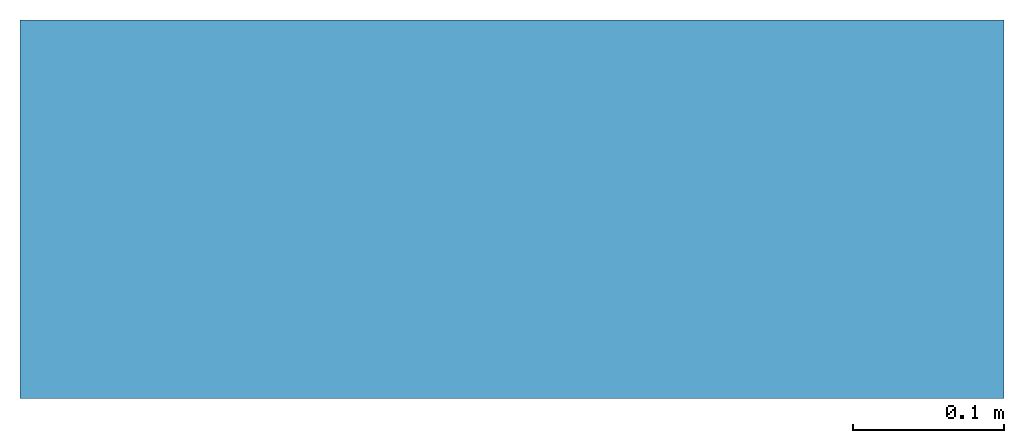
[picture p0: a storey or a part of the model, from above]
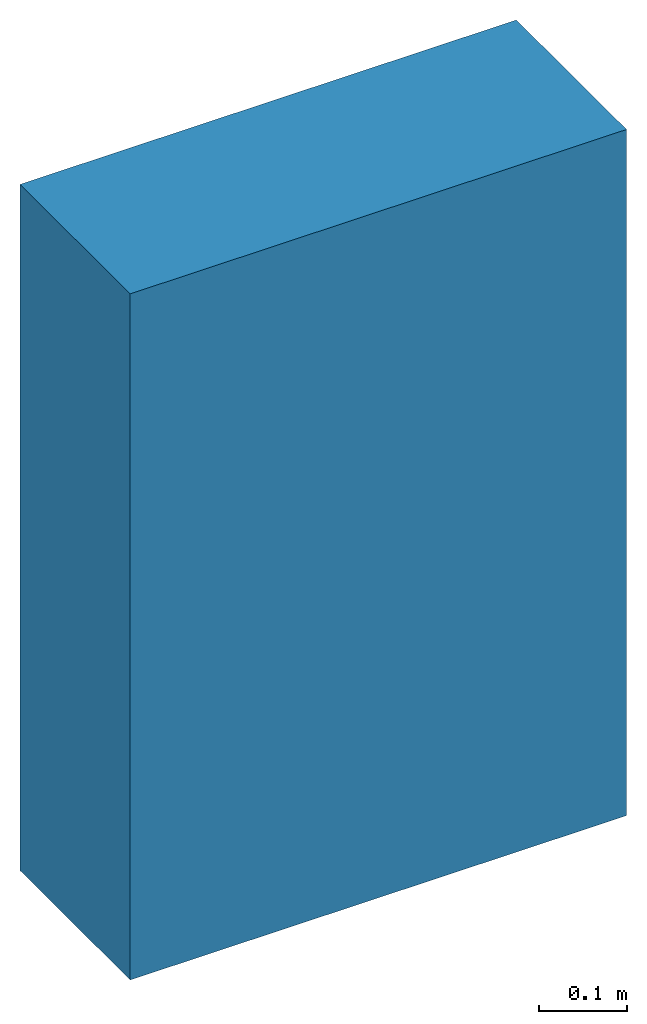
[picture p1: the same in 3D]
Properties of the parts of a building model (IFC2X3), part 1 of 2

# File
Description: ViewDefinition [CoordinationView]
File name: VA001-350.101.1 (EDITED).ifc (Edited by Naviate Simple BIM 2022 version 6)
Time: 2026-03-20T14:23:33+01:00
Written by: ODA SDAI 22.12
Made in: Autodesk Revit 23.1.90.15 (ENU) - IFC 23.3.1.0

# IfcProject
LongName: Trondheim Lufthavn Værnes; Phase: TU 2013

# IfcSite, Default
RefLatitude: 59, 54, 57, 601318; RefLongitude: 10, 44, 59, 999999; RefElevation: 0 mm
Data - Ideate BIMLink: <?xml version="1.0" encoding="utf-8"?><application version="3"> <links> <link> <name>Casework Types</name> <description></description> <elements>CaseworkTypes</elements> <phase>Fase 2</phase> <phase_filter>None</phase_filter> <properties> <property> <name>Id</name> <lookup_1_type></lookup_1_type> <lookup_1_id></lookup_1_id> <type>BUILT_IN_PARAMETER</type> <id>ID_PARAM</id> </property> <property> <name>Family Name</name> <lookup_1_type></lookup_1_type> <lookup_1_id></lookup_1_id> <type>CALCULATED_PROPERTY</type> <id>FamilyName</id> </property> <property> <name>Type Name</name> <lookup_1_type></lookup_1_type> <lookup_1_id></lookup_1_id> <type>CALCULATED_PROPERTY</type> <id>TypeName</id> </property> </properties> </link> <link> <name>Window Types</name> <description></description> <elements>WindowTypes</elements> <phase>Fase 2</phase> <phase_filter>None</phase_filter> <properties> <property> <name>Id</name> <lookup_1_type></lookup_1_type> <lookup_1_id></lookup_1_id> <type>BUILT_IN_PARAMETER</type> <id>ID_PARAM</id> </property> <property> <name>Family Name</name> <lookup_1_type></lookup_1_type> <lookup_1_id></lookup_1_id> <type>CALCULATED_PROPERTY</type> <id>FamilyName</id> </property> <property> <name>Type Name</name> <lookup_1_type></lookup_1_type> <lookup_1_id></lookup_1_id> <type>CALCULATED_PROPERTY</type> <id>TypeName</id> </property> </properties> </link> <link> <name>Wall Types</name> <description></description> <elements>WallTypes</elements> <phase>Fase 1</phase> <phase_filter>Show Complete</phase_filter> <properties> <property> <name>Id</name> <lookup_1_type></lookup_1_type> <lookup_1_id></lookup_1_id> <type>BUILT_IN_PARAMETER</type> <id>ID_PARAM</id> </property> <property> <name>Family Name</name> <lookup_1_type></lookup_1_type> <lookup_1_id></lookup_1_id> <type>BUILT_IN_PARAMETER</type> <id>SYMBOL_FAMILY_NAME_PARAM</id> </property> <property> <name>Type Name</name> <lookup_1_type></lookup_1_type> <lookup_1_id></lookup_1_id> <type>CALCULATED_PROPERTY</type> <id>TypeName</id> </property> </properties> </link> <link> <name>Structural Framing Types</name> <description></description> <elements>StructuralFramingTypes</elements> <phase>Fase 2</phase> <phase_filter>None</phase_filter> <properties> <property> <name>Id</name> <lookup_1_type></lookup_1_type> <lookup_1_id></lookup_1_id> <type>BUILT_IN_PARAMETER</type> <id>ID_PARAM</id> </property> <property> <name>Family Name</name> <lookup_1_type></lookup_1_type> <lookup_1_id></lookup_1_id> <type>CALCULATED_PROPERTY</type> <id>FamilyName</id> </property> <property> <name>Type Name</name> <lookup_1_type></lookup_1_type> <lookup_1_id></lookup_1_id> <type>CALCULATED_PROPERTY</type> <id>TypeName</id> </property> </properties> </link> <link> <name>Structural Foundation Types</name> <description></description> <elements>StructuralFoundationTypes</elements> <phase>Fase 2</phase> <phase_filter>None</phase_filter> <properties> <property> <name>Id</name> <lookup_1_type></lookup_1_type> <lookup_1_id></lookup_1_id> <type>BUILT_IN_PARAMETER</type> <id>ID_PARAM</id> </property> <property> <name>Family Name</name> <lookup_1_type></lookup_1_type> <lookup_1_id></lookup_1_id> <type>CALCULATED_PROPERTY</type> <id>FamilyName</id> </property> <property> <name>Type Name</name> <lookup_1_type></lookup_1_type> <lookup_1_id></lookup_1_id> <type>CALCULATED_PROPERTY</type> <id>TypeName</id> </property> </properties> </link> <link> <name>Structural Column Types</name> <description></description> <elements>StructuralColumnTypes</elements> <phase>Fase 2</phase> <phase_filter>None</phase_filter> <properties> <property> <name>Id</name> <lookup_1_type></lookup_1_type> <lookup_1_id></lookup_1_id> <type>BUILT_IN_PARAMETER</type> <id>ID_PARAM</id> </property> <property> <name>Family Name</name> <lookup_1_type></lookup_1_type> <lookup_1_id></lookup_1_id> <type>CALCULATED_PROPERTY</type> <id>FamilyName</id> </property> <property> <name>Type Name</name> <lookup_1_type></lookup_1_type> <lookup_1_id></lookup_1_id> <type>CALCULATED_PROPERTY</type> <id>TypeName</id> </property> </properties> </link> <link> <name>Stair Types</name> <description></description> <elements>StairTypes</elements> <phase>Fase 2</phase> <phase_filter>None</phase_filter> <properties> <property> <name>Id</name> <lookup_1_type></lookup_1_type> <lookup_1_id></lookup_1_id> <type>BUILT_IN_PARAMETER</type> <id>ID_PARAM</id> </property> <property> <name>Family Name</name> <lookup_1_type></lookup_1_type> <lookup_1_id></lookup_1_id> <type>BUILT_IN_PARAMETER</type> <id>ALL_MODEL_FAMILY_NAME</id> </property> <property> <name>Type Name</name> <lookup_1_type></lookup_1_type> <lookup_1_id></lookup_1_id> <type>CALCULATED_PROPERTY</type> <id>TypeName</id> </property> </properties> </link> <link> <name>Specialty Equipment Types</name> <description></description> <elements>SpecialtyEquipmentTypes</elements> <phase>Fase 2</phase> <phase_filter>None</phase_filter> <properties> <property> <name>Id</name> <lookup_1_type></lookup_1_type> <lookup_1_id></lookup_1_id> <type>BUILT_IN_PARAMETER</type> <id>ID_PARAM</id> </property> <property> <name>Family Name</name> <lookup_1_type></lookup_1_type> <lookup_1_id></lookup_1_id> <type>CALCULATED_PROPERTY</type> <id>FamilyName</id> </property> <property> <name>Type Name</name> <lookup_1_type></lookup_1_type> <lookup_1_id></lookup_1_id> <type>CALCULATED_PROPERTY</type> <id>TypeName</id> </property> </properties> </link> <link> <name>Roof Types</name> <description></description> <elements>RoofTypes</elements> <phase>Fase 2</phase> <phase_filter>None</phase_filter> <properties> <property> <name>Id</name> <lookup_1_type></lookup_1_type> <lookup_1_id></lookup_1_id> <type>BUILT_IN_PARAMETER</type> <id>ID_PARAM</id> </property> <property> <name>Family Name</name> <lookup_1_type></lookup_1_type> <lookup_1_id></lookup_1_id> <type>BUILT_IN_PARAMETER</type> <id>ALL_MODEL_FAMILY_NAME</id> </property> <property> <name>Type Name</name> <lookup_1_type></lookup_1_type> <lookup_1_id></lookup_1_id> <type>CALCULATED_PROPERTY</type> <id>TypeName</id> </property> </properties> </link> <link> <name>Ramp Types</name> <description></description> <elements>RampTypes</elements> <phase>Fase 2</phase> <phase_filter>None</phase_filter> <properties> <property> <name>Id</name> <lookup_1_type></lookup_1_type> <lookup_1_id></lookup_1_id> <type>BUILT_IN_PARAMETER</type> <id>ID_PARAM</id> </property> <property> <name>Family Name</name> <lookup_1_type></lookup_1_type> <lookup_1_id></lookup_1_id> <type>BUILT_IN_PARAMETER</type> <id>ALL_MODEL_FAMILY_NAME</id> </property> <property> <name>Type Name</name> <lookup_1_type></lookup_1_type> <lookup_1_id></lookup_1_id> <type>CALCULATED_PROPERTY</type> <id>TypeName</id> </property> </properties> </link> <link> <name>Railing Types</name> <description></description> <elements>RailingTypes</elements> <phase>Fase 2</phase> <phase_filter>None</phase_filter> <properties> <property> <name>Id</name> <lookup_1_type></lookup_1_type> <lookup_1_id></lookup_1_id> <type>BUILT_IN_PARAMETER</type> <id>ID_PARAM</id> </property> <property> <name>Family Name</name> <lookup_1_type></lookup_1_type> <lookup_1_id></lookup_1_id> <type>BUILT_IN_PARAMETER</type> <id>ALL_MODEL_FAMILY_NAME</id> </property> <property> <name>Type Name</name> <lookup_1_type></lookup_1_type> <lookup_1_id></lookup_1_id> <type>CALCULATED_PROPERTY</type> <id>TypeName</id> </property> </properties> </link> <link> <name>Profile Types</name> <description></description> <elements>ProfileTypes</elements> <phase>Fase 2</phase> <phase_filter>None</phase_filter> <properties> <property> <name>Id</name> <lookup_1_type></lookup_1_type> <lookup_1_id></lookup_1_id> <type>BUILT_IN_PARAMETER</type> <id>ID_PARAM</id> </property> <property> <name>Family Name</name> <lookup_1_type></lookup_1_type> <lookup_1_id></lookup_1_id> <type>BUILT_IN_PARAMETER</type> <id>ALL_MODEL_FAMILY_NAME</id> </property> <property> <name>Type Name</name> <lookup_1_type></lookup_1_type> <lookup_1_id></lookup_1_id> <type>CALCULATED_PROPERTY</type> <id>TypeName</id> </property> </properties> </link> <link> <name>Plumbing Fixture Types</name> <description></description> <elements>PlumbingFixtureTypes</elements> <phase>Fase 2</phase> <phase_filter>None</phase_filter> <properties> <property> <name>Id</name> <lookup_1_type></lookup_1_type> <lookup_1_id></lookup_1_id> <type>BUILT_IN_PARAMETER</type> <id>ID_PARAM</id> </property> <property> <name>Family Name</name> <lookup_1_type></lookup_1_type> <lookup_1_id></lookup_1_id> <type>CALCULATED_PROPERTY</type> <id>FamilyName</id> </property> <property> <name>Type Name</name> <lookup_1_type></lookup_1_type> <lookup_1_id></lookup_1_id> <type>CALCULATED_PROPERTY</type> <id>TypeName</id> </property> </properties> </link> <link> <name>Mechanical Equipment Types</name> <description></description> <elements>MechanicalEquipmentTypes</elements> <phase>Fase 2</phase> <phase_filter>None</phase_filter> <properties> <property> <name>Id</name> <lookup_1_type></lookup_1_type> <lookup_1_id></lookup_1_id> <type>BUILT_IN_PARAMETER</type> <id>ID_PARAM</id> </property> <property> <name>Family Name</name> <lookup_1_type></lookup_1_type> <lookup_1_id></lookup_1_id> <type>CALCULATED_PROPERTY</type> <id>FamilyName</id> </property> <property> <name>Type Name</name> <lookup_1_type></lookup_1_type> <lookup_1_id></lookup_1_id> <type>CALCULATED_PROPERTY</type> <id>TypeName</id> </property> </properties> </link> <link> <name>Mass Types</name> <description></description> <elements>MassTypes</elements> <phase>Fase 2</phase> <phase_filter>None</phase_filter> <properties> <property> <name>Id</name> <lookup_1_type></lookup_1_type> <lookup_1_id></lookup_1_id> <type>BUILT_IN_PARAMETER</type> <id>ID_PARAM</id> </property> <property> <name>Family Name</name> <lookup_1_type></lookup_1_type> <lookup_1_id></lookup_1_id> <type>CALCULATED_PROPERTY</type> <id>FamilyName</id> </property> <property> <name>Type Name</name> <lookup_1_type></lookup_1_type> <lookup_1_id></lookup_1_id> <type>CALCULATED_PROPERTY</type> <id>TypeName</id> </property> </properties> </link> <link> <name>Generic Model Types</name> <description></description> <elements>GenericModelTypes</elements> <phase>Fase 2</phase> <phase_filter>None</phase_filter> <properties> <property> <name>Id</name> <lookup_1_type></lookup_1_type> <lookup_1_id></lookup_1_id> <type>BUILT_IN_PARAMETER</type> <id>ID_PARAM</id> </property> <property> <name>Family Name</name> <lookup_1_type></lookup_1_type> <lookup_1_id></lookup_1_id> <type>CALCULATED_PROPERTY</type> <id>FamilyName</id> </property> <property> <name>Type Name</name> <lookup_1_type></lookup_1_type> <lookup_1_id></lookup_1_id> <type>CALCULATED_PROPERTY</type> <id>TypeName</id> </property> </properties> </link> <link> <name>Column Types</name> <description></description> <elements>ColumnTypes</elements> <phase>Fase 2</phase> <phase_filter>None</phase_filter> <properties> <property> <name>Id</name> <lookup_1_type></lookup_1_type> <lookup_1_id></lookup_1_id> <type>BUILT_IN_PARAMETER</type> <id>ID_PARAM</id> </property> <property> <name>Family Name</name> <lookup_1_type></lookup_1_type> <lookup_1_id></lookup_1_id> <type>CALCULATED_PROPERTY</type> <id>FamilyName</id> </property> <property> <name>Type Name</name> <lookup_1_type></lookup_1_type> <lookup_1_id></lookup_1_id> <type>CALCULATED_PROPERTY</type> <id>TypeName</id> </property> </properties> </link> <link> <name>Columns</name> <description></description> <elements>ColumnInstances</elements> <phase>Fase 2</phase> <phase_filter>None</phase_filter> <properties> <property> <name>Id</name> <lookup_1_type></lookup_1_type> <lookup_1_id></lookup_1_id> <type>BUILT_IN_PARAMETER</type> <id>ID_PARAM</id> </property> </properties> </link> <link> <name>Door Types</name> <description></description> <elements>DoorTypes</elements> <phase>Fase 2</phase> <phase_filter>None</phase_filter> <properties> <property> <name>Id</name> <lookup_1_type></lookup_1_type> <lookup_1_id></lookup_1_id> <type>BUILT_IN_PARAMETER</type> <id>ID_PARAM</id> </property> <property> <name>Family Name</name> <lookup_1_type></lookup_1_type> <lookup_1_id></lookup_1_id> <type>CALCULATED_PROPERTY</type> <id>FamilyName</id> </property> <property> <name>Type Name</name> <lookup_1_type></lookup_1_type> <lookup_1_id></lookup_1_id> <type>CALCULATED_PROPERTY</type> <id>TypeName</id> </property> </properties> </link> <link> <name>Door Types 2</name> <description></description> <elements>DoorTypes</elements> <phase>Fase 1</phase> <phase_filter>Show Complete</phase_filter> <properties> <property> <name>Id</name> <lookup_1_type></lookup_1_type> <lookup_1_id></lookup_1_id> <type>BUILT_IN_PARAMETER</type> <id>ID_PARAM</id> </property> <property> <name>Family Name</name> <lookup_1_type></lookup_1_type> <lookup_1_id></lookup_1_id> <type>CALCULATED_PROPERTY</type> <id>FamilyName</id> </property> <property> <name>Type Name</name> <lookup_1_type></lookup_1_type> <lookup_1_id></lookup_1_id> <type>CALCULATED_PROPERTY</type> <id>TypeName</id> </property> </properties> </link> <link> <name>Ceiling Types</name> <description></description> <elements>CeilingTypes</elements> <phase>Fase 2</phase> <phase_filter>None</phase_filter> <properties> <property> <name>Id</name> <lookup_1_type></lookup_1_type> <lookup_1_id></lookup_1_id> <type>BUILT_IN_PARAMETER</type> <id>ID_PARAM</id> </property> <property> <name>Family Name</name> <lookup_1_type></lookup_1_type> <lookup_1_id></lookup_1_id> <type>BUILT_IN_PARAMETER</type> <id>ALL_MODEL_FAMILY_NAME</id> </property> <property> <name>Type Name</name> <lookup_1_type></lookup_1_type> <lookup_1_id></lookup_1_id> <type>CALCULATED_PROPERTY</type> <id>TypeName</id> </property> </properties> </link> <link> <name>Ceilings</name> <description></description> <elements>CeilingInstances</elements> <phase>Fase 2</phase> <phase_filter>None</phase_filter> <properties> <property> <name>Id</name> <lookup_1_type></lookup_1_type> <lookup_1_id></lookup_1_id> <type>BUILT_IN_PARAMETER</type> <id>ID_PARAM</id> </property> <property> <name>Family Name</name> <lookup_1_type>BUILT_IN_PARAMETER</lookup_1_type> <lookup_1_id>SYMBOL_ID_PARAM</lookup_1_id> <type>BUILT_IN_PARAMETER</type> <id>ALL_MODEL_FAMILY_NAME</id> </property> <property> <name>Type Name</name> <lookup_1_type>BUILT_IN_PARAMETER</lookup_1_type> <lookup_1_id>SYMBOL_ID_PARAM</lookup_1_id> <type>CALCULATED_PROPERTY</type> <id>TypeName</id> </property> </properties> </link> <link> <name>Furniture Types</name> <description></description> <elements>FurnitureTypes</elements> <phase>Fase 2</phase> <phase_filter>None</phase_filter> <properties> <property> <name>Id</name> <lookup_1_type></lookup_1_type> <lookup_1_id></lookup_1_id> <type>BUILT_IN_PARAMETER</type> <id>ID_PARAM</id> </property> <property> <name>Family Name</name> <lookup_1_type></lookup_1_type> <lookup_1_id></lookup_1_id> <type>CALCULATED_PROPERTY</type> <id>FamilyName</id> </property> <property> <name>Type Name</name> <lookup_1_type></lookup_1_type> <lookup_1_id></lookup_1_id> <type>CALCULATED_PROPERTY</type> <id>TypeName</id> </property> </properties> </link> <link> <name>Furniture System Types</name> <description></description> <elements>FurnitureSystemTypes</elements> <phase>Fase 2</phase> <phase_filter>None</phase_filter> <properties> <property> <name>Id</name> <lookup_1_type></lookup_1_type> <lookup_1_id></lookup_1_id> <type>BUILT_IN_PARAMETER</type> <id>ID_PARAM</id> </property> <property> <name>Family Name</name> <lookup_1_type></lookup_1_type> <lookup_1_id></lookup_1_id> <type>CALCULATED_PROPERTY</type> <id>FamilyName</id> </property> <property> <name>Type Name</name> <lookup_1_type></lookup_1_type> <lookup_1_id></lookup_1_id> <type>CALCULATED_PROPERTY</type> <id>TypeName</id> </property> </properties> </link> <link> <name>Sheets</name> <description></description> <elements>Sheets</elements> <phase>Fase 1</phase> <phase_filter>None</phase_filter> <properties> <property> <name>Id</name> <lookup_1_type></lookup_1_type> <lookup_1_id></lookup_1_id> <type>BUILT_IN_PARAMETER</type> <id>ID_PARAM</id> </property> </properties> </link> <link> <name>Walls</name> <description></description> <elements>WallInstances</elements> <phase>Fase 2</phase> <phase_filter>None</phase_filter> <properties> <property> <name>Id</name> <lookup_1_type></lookup_1_type> <lookup_1_id></lookup_1_id> <type>BUILT_IN_PARAMETER</type> <id>ID_PARAM</id> </property> </properties> </link> <link> <name>Wall types all official names</name> <description></description> <elements>WallTypes</elements> <phase>Fase 1</phase> <phase_filter>None</phase_filter> <properties> <property> <name>Id</name> <lookup_1_type></lookup_1_type> <lookup_1_id></lookup_1_id> <type>BUILT_IN_PARAMETER</type> <id>ID_PARAM</id> </property> <property> <name>Family Name</name> <lookup_1_type></lookup_1_type> <lookup_1_id></lookup_1_id> <type>BUILT_IN_PARAMETER</type> <id>ALL_MODEL_FAMILY_NAME</id> </property> <property> <name>Type Name</name> <lookup_1_type></lookup_1_type> <lookup_1_id></lookup_1_id> <type>CALCULATED_PROPERTY</type> <id>TypeName</id> </property> </properties> </link> <link> <name>test</name> <description></description> <elements>WallTypes</elements> <phase>Fase 1</phase> <phase_filter>None</phase_filter> <properties> <property> <name>Id</name> <lookup_1_type></lookup_1_type> <lookup_1_id></lookup_1_id> <type>BUILT_IN_PARAMETER</type> <id>ID_PARAM</id> </property> <property> <name>Family Name</name> <lookup_1_type></lookup_1_type> <lookup_1_id></lookup_1_id> <type>BUILT_IN_PARAMETER</type> <id>ALL_MODEL_FAMILY_NAME</id> </property> <property> <name>Type Name</name> <lookup_1_type></lookup_1_type> <lookup_1_id></lookup_1_id> <type>CALCULATED_PROPERTY</type> <id>TypeName</id> </property> </properties> </link> </links></application>
Identity Data - Workset: Project Info
Text - 01_Modellfil: va006-a-220-1-0001.rvt
Other - RIE, firma: RAMBØLL AS; Project Status: TU 2013; Saksbehandler: MR; Project Address: Skriv adresse her; Category: Project Information; Prosjektansvarlig: TILBUD E203 TETT BYGG; RIV, telefon: +47 7310 6200; RIB, telefon: +47 7289 3750; Project Name: Trondheim Lufthavn Værnes; RIV, firma: MULTICONSULT AS; RIB, firma: NORCONSULT; RIE, telefon: +47 7389 1000

# IfcBuilding
Pset_BuildingCommon - NumberOfStoreys: 7
Data - Ideate BIMLink: <?xml version="1.0" encoding="utf-8"?><application version="3"> <links> <link> <name>Casework Types</name> <description></description> <elements>CaseworkTypes</elements> <phase>Fase 2</phase> <phase_filter>None</phase_filter> <properties> <property> <name>Id</name> <lookup_1_type></lookup_1_type> <lookup_1_id></lookup_1_id> <type>BUILT_IN_PARAMETER</type> <id>ID_PARAM</id> </property> <property> <name>Family Name</name> <lookup_1_type></lookup_1_type> <lookup_1_id></lookup_1_id> <type>CALCULATED_PROPERTY</type> <id>FamilyName</id> </property> <property> <name>Type Name</name> <lookup_1_type></lookup_1_type> <lookup_1_id></lookup_1_id> <type>CALCULATED_PROPERTY</type> <id>TypeName</id> </property> </properties> </link> <link> <name>Window Types</name> <description></description> <elements>WindowTypes</elements> <phase>Fase 2</phase> <phase_filter>None</phase_filter> <properties> <property> <name>Id</name> <lookup_1_type></lookup_1_type> <lookup_1_id></lookup_1_id> <type>BUILT_IN_PARAMETER</type> <id>ID_PARAM</id> </property> <property> <name>Family Name</name> <lookup_1_type></lookup_1_type> <lookup_1_id></lookup_1_id> <type>CALCULATED_PROPERTY</type> <id>FamilyName</id> </property> <property> <name>Type Name</name> <lookup_1_type></lookup_1_type> <lookup_1_id></lookup_1_id> <type>CALCULATED_PROPERTY</type> <id>TypeName</id> </property> </properties> </link> <link> <name>Wall Types</name> <description></description> <elements>WallTypes</elements> <phase>Fase 1</phase> <phase_filter>Show Complete</phase_filter> <properties> <property> <name>Id</name> <lookup_1_type></lookup_1_type> <lookup_1_id></lookup_1_id> <type>BUILT_IN_PARAMETER</type> <id>ID_PARAM</id> </property> <property> <name>Family Name</name> <lookup_1_type></lookup_1_type> <lookup_1_id></lookup_1_id> <type>BUILT_IN_PARAMETER</type> <id>SYMBOL_FAMILY_NAME_PARAM</id> </property> <property> <name>Type Name</name> <lookup_1_type></lookup_1_type> <lookup_1_id></lookup_1_id> <type>CALCULATED_PROPERTY</type> <id>TypeName</id> </property> </properties> </link> <link> <name>Structural Framing Types</name> <description></description> <elements>StructuralFramingTypes</elements> <phase>Fase 2</phase> <phase_filter>None</phase_filter> <properties> <property> <name>Id</name> <lookup_1_type></lookup_1_type> <lookup_1_id></lookup_1_id> <type>BUILT_IN_PARAMETER</type> <id>ID_PARAM</id> </property> <property> <name>Family Name</name> <lookup_1_type></lookup_1_type> <lookup_1_id></lookup_1_id> <type>CALCULATED_PROPERTY</type> <id>FamilyName</id> </property> <property> <name>Type Name</name> <lookup_1_type></lookup_1_type> <lookup_1_id></lookup_1_id> <type>CALCULATED_PROPERTY</type> <id>TypeName</id> </property> </properties> </link> <link> <name>Structural Foundation Types</name> <description></description> <elements>StructuralFoundationTypes</elements> <phase>Fase 2</phase> <phase_filter>None</phase_filter> <properties> <property> <name>Id</name> <lookup_1_type></lookup_1_type> <lookup_1_id></lookup_1_id> <type>BUILT_IN_PARAMETER</type> <id>ID_PARAM</id> </property> <property> <name>Family Name</name> <lookup_1_type></lookup_1_type> <lookup_1_id></lookup_1_id> <type>CALCULATED_PROPERTY</type> <id>FamilyName</id> </property> <property> <name>Type Name</name> <lookup_1_type></lookup_1_type> <lookup_1_id></lookup_1_id> <type>CALCULATED_PROPERTY</type> <id>TypeName</id> </property> </properties> </link> <link> <name>Structural Column Types</name> <description></description> <elements>StructuralColumnTypes</elements> <phase>Fase 2</phase> <phase_filter>None</phase_filter> <properties> <property> <name>Id</name> <lookup_1_type></lookup_1_type> <lookup_1_id></lookup_1_id> <type>BUILT_IN_PARAMETER</type> <id>ID_PARAM</id> </property> <property> <name>Family Name</name> <lookup_1_type></lookup_1_type> <lookup_1_id></lookup_1_id> <type>CALCULATED_PROPERTY</type> <id>FamilyName</id> </property> <property> <name>Type Name</name> <lookup_1_type></lookup_1_type> <lookup_1_id></lookup_1_id> <type>CALCULATED_PROPERTY</type> <id>TypeName</id> </property> </properties> </link> <link> <name>Stair Types</name> <description></description> <elements>StairTypes</elements> <phase>Fase 2</phase> <phase_filter>None</phase_filter> <properties> <property> <name>Id</name> <lookup_1_type></lookup_1_type> <lookup_1_id></lookup_1_id> <type>BUILT_IN_PARAMETER</type> <id>ID_PARAM</id> </property> <property> <name>Family Name</name> <lookup_1_type></lookup_1_type> <lookup_1_id></lookup_1_id> <type>BUILT_IN_PARAMETER</type> <id>ALL_MODEL_FAMILY_NAME</id> </property> <property> <name>Type Name</name> <lookup_1_type></lookup_1_type> <lookup_1_id></lookup_1_id> <type>CALCULATED_PROPERTY</type> <id>TypeName</id> </property> </properties> </link> <link> <name>Specialty Equipment Types</name> <description></description> <elements>SpecialtyEquipmentTypes</elements> <phase>Fase 2</phase> <phase_filter>None</phase_filter> <properties> <property> <name>Id</name> <lookup_1_type></lookup_1_type> <lookup_1_id></lookup_1_id> <type>BUILT_IN_PARAMETER</type> <id>ID_PARAM</id> </property> <property> <name>Family Name</name> <lookup_1_type></lookup_1_type> <lookup_1_id></lookup_1_id> <type>CALCULATED_PROPERTY</type> <id>FamilyName</id> </property> <property> <name>Type Name</name> <lookup_1_type></lookup_1_type> <lookup_1_id></lookup_1_id> <type>CALCULATED_PROPERTY</type> <id>TypeName</id> </property> </properties> </link> <link> <name>Roof Types</name> <description></description> <elements>RoofTypes</elements> <phase>Fase 2</phase> <phase_filter>None</phase_filter> <properties> <property> <name>Id</name> <lookup_1_type></lookup_1_type> <lookup_1_id></lookup_1_id> <type>BUILT_IN_PARAMETER</type> <id>ID_PARAM</id> </property> <property> <name>Family Name</name> <lookup_1_type></lookup_1_type> <lookup_1_id></lookup_1_id> <type>BUILT_IN_PARAMETER</type> <id>ALL_MODEL_FAMILY_NAME</id> </property> <property> <name>Type Name</name> <lookup_1_type></lookup_1_type> <lookup_1_id></lookup_1_id> <type>CALCULATED_PROPERTY</type> <id>TypeName</id> </property> </properties> </link> <link> <name>Ramp Types</name> <description></description> <elements>RampTypes</elements> <phase>Fase 2</phase> <phase_filter>None</phase_filter> <properties> <property> <name>Id</name> <lookup_1_type></lookup_1_type> <lookup_1_id></lookup_1_id> <type>BUILT_IN_PARAMETER</type> <id>ID_PARAM</id> </property> <property> <name>Family Name</name> <lookup_1_type></lookup_1_type> <lookup_1_id></lookup_1_id> <type>BUILT_IN_PARAMETER</type> <id>ALL_MODEL_FAMILY_NAME</id> </property> <property> <name>Type Name</name> <lookup_1_type></lookup_1_type> <lookup_1_id></lookup_1_id> <type>CALCULATED_PROPERTY</type> <id>TypeName</id> </property> </properties> </link> <link> <name>Railing Types</name> <description></description> <elements>RailingTypes</elements> <phase>Fase 2</phase> <phase_filter>None</phase_filter> <properties> <property> <name>Id</name> <lookup_1_type></lookup_1_type> <lookup_1_id></lookup_1_id> <type>BUILT_IN_PARAMETER</type> <id>ID_PARAM</id> </property> <property> <name>Family Name</name> <lookup_1_type></lookup_1_type> <lookup_1_id></lookup_1_id> <type>BUILT_IN_PARAMETER</type> <id>ALL_MODEL_FAMILY_NAME</id> </property> <property> <name>Type Name</name> <lookup_1_type></lookup_1_type> <lookup_1_id></lookup_1_id> <type>CALCULATED_PROPERTY</type> <id>TypeName</id> </property> </properties> </link> <link> <name>Profile Types</name> <description></description> <elements>ProfileTypes</elements> <phase>Fase 2</phase> <phase_filter>None</phase_filter> <properties> <property> <name>Id</name> <lookup_1_type></lookup_1_type> <lookup_1_id></lookup_1_id> <type>BUILT_IN_PARAMETER</type> <id>ID_PARAM</id> </property> <property> <name>Family Name</name> <lookup_1_type></lookup_1_type> <lookup_1_id></lookup_1_id> <type>BUILT_IN_PARAMETER</type> <id>ALL_MODEL_FAMILY_NAME</id> </property> <property> <name>Type Name</name> <lookup_1_type></lookup_1_type> <lookup_1_id></lookup_1_id> <type>CALCULATED_PROPERTY</type> <id>TypeName</id> </property> </properties> </link> <link> <name>Plumbing Fixture Types</name> <description></description> <elements>PlumbingFixtureTypes</elements> <phase>Fase 2</phase> <phase_filter>None</phase_filter> <properties> <property> <name>Id</name> <lookup_1_type></lookup_1_type> <lookup_1_id></lookup_1_id> <type>BUILT_IN_PARAMETER</type> <id>ID_PARAM</id> </property> <property> <name>Family Name</name> <lookup_1_type></lookup_1_type> <lookup_1_id></lookup_1_id> <type>CALCULATED_PROPERTY</type> <id>FamilyName</id> </property> <property> <name>Type Name</name> <lookup_1_type></lookup_1_type> <lookup_1_id></lookup_1_id> <type>CALCULATED_PROPERTY</type> <id>TypeName</id> </property> </properties> </link> <link> <name>Mechanical Equipment Types</name> <description></description> <elements>MechanicalEquipmentTypes</elements> <phase>Fase 2</phase> <phase_filter>None</phase_filter> <properties> <property> <name>Id</name> <lookup_1_type></lookup_1_type> <lookup_1_id></lookup_1_id> <type>BUILT_IN_PARAMETER</type> <id>ID_PARAM</id> </property> <property> <name>Family Name</name> <lookup_1_type></lookup_1_type> <lookup_1_id></lookup_1_id> <type>CALCULATED_PROPERTY</type> <id>FamilyName</id> </property> <property> <name>Type Name</name> <lookup_1_type></lookup_1_type> <lookup_1_id></lookup_1_id> <type>CALCULATED_PROPERTY</type> <id>TypeName</id> </property> </properties> </link> <link> <name>Mass Types</name> <description></description> <elements>MassTypes</elements> <phase>Fase 2</phase> <phase_filter>None</phase_filter> <properties> <property> <name>Id</name> <lookup_1_type></lookup_1_type> <lookup_1_id></lookup_1_id> <type>BUILT_IN_PARAMETER</type> <id>ID_PARAM</id> </property> <property> <name>Family Name</name> <lookup_1_type></lookup_1_type> <lookup_1_id></lookup_1_id> <type>CALCULATED_PROPERTY</type> <id>FamilyName</id> </property> <property> <name>Type Name</name> <lookup_1_type></lookup_1_type> <lookup_1_id></lookup_1_id> <type>CALCULATED_PROPERTY</type> <id>TypeName</id> </property> </properties> </link> <link> <name>Generic Model Types</name> <description></description> <elements>GenericModelTypes</elements> <phase>Fase 2</phase> <phase_filter>None</phase_filter> <properties> <property> <name>Id</name> <lookup_1_type></lookup_1_type> <lookup_1_id></lookup_1_id> <type>BUILT_IN_PARAMETER</type> <id>ID_PARAM</id> </property> <property> <name>Family Name</name> <lookup_1_type></lookup_1_type> <lookup_1_id></lookup_1_id> <type>CALCULATED_PROPERTY</type> <id>FamilyName</id> </property> <property> <name>Type Name</name> <lookup_1_type></lookup_1_type> <lookup_1_id></lookup_1_id> <type>CALCULATED_PROPERTY</type> <id>TypeName</id> </property> </properties> </link> <link> <name>Column Types</name> <description></description> <elements>ColumnTypes</elements> <phase>Fase 2</phase> <phase_filter>None</phase_filter> <properties> <property> <name>Id</name> <lookup_1_type></lookup_1_type> <lookup_1_id></lookup_1_id> <type>BUILT_IN_PARAMETER</type> <id>ID_PARAM</id> </property> <property> <name>Family Name</name> <lookup_1_type></lookup_1_type> <lookup_1_id></lookup_1_id> <type>CALCULATED_PROPERTY</type> <id>FamilyName</id> </property> <property> <name>Type Name</name> <lookup_1_type></lookup_1_type> <lookup_1_id></lookup_1_id> <type>CALCULATED_PROPERTY</type> <id>TypeName</id> </property> </properties> </link> <link> <name>Columns</name> <description></description> <elements>ColumnInstances</elements> <phase>Fase 2</phase> <phase_filter>None</phase_filter> <properties> <property> <name>Id</name> <lookup_1_type></lookup_1_type> <lookup_1_id></lookup_1_id> <type>BUILT_IN_PARAMETER</type> <id>ID_PARAM</id> </property> </properties> </link> <link> <name>Door Types</name> <description></description> <elements>DoorTypes</elements> <phase>Fase 2</phase> <phase_filter>None</phase_filter> <properties> <property> <name>Id</name> <lookup_1_type></lookup_1_type> <lookup_1_id></lookup_1_id> <type>BUILT_IN_PARAMETER</type> <id>ID_PARAM</id> </property> <property> <name>Family Name</name> <lookup_1_type></lookup_1_type> <lookup_1_id></lookup_1_id> <type>CALCULATED_PROPERTY</type> <id>FamilyName</id> </property> <property> <name>Type Name</name> <lookup_1_type></lookup_1_type> <lookup_1_id></lookup_1_id> <type>CALCULATED_PROPERTY</type> <id>TypeName</id> </property> </properties> </link> <link> <name>Door Types 2</name> <description></description> <elements>DoorTypes</elements> <phase>Fase 1</phase> <phase_filter>Show Complete</phase_filter> <properties> <property> <name>Id</name> <lookup_1_type></lookup_1_type> <lookup_1_id></lookup_1_id> <type>BUILT_IN_PARAMETER</type> <id>ID_PARAM</id> </property> <property> <name>Family Name</name> <lookup_1_type></lookup_1_type> <lookup_1_id></lookup_1_id> <type>CALCULATED_PROPERTY</type> <id>FamilyName</id> </property> <property> <name>Type Name</name> <lookup_1_type></lookup_1_type> <lookup_1_id></lookup_1_id> <type>CALCULATED_PROPERTY</type> <id>TypeName</id> </property> </properties> </link> <link> <name>Ceiling Types</name> <description></description> <elements>CeilingTypes</elements> <phase>Fase 2</phase> <phase_filter>None</phase_filter> <properties> <property> <name>Id</name> <lookup_1_type></lookup_1_type> <lookup_1_id></lookup_1_id> <type>BUILT_IN_PARAMETER</type> <id>ID_PARAM</id> </property> <property> <name>Family Name</name> <lookup_1_type></lookup_1_type> <lookup_1_id></lookup_1_id> <type>BUILT_IN_PARAMETER</type> <id>ALL_MODEL_FAMILY_NAME</id> </property> <property> <name>Type Name</name> <lookup_1_type></lookup_1_type> <lookup_1_id></lookup_1_id> <type>CALCULATED_PROPERTY</type> <id>TypeName</id> </property> </properties> </link> <link> <name>Ceilings</name> <description></description> <elements>CeilingInstances</elements> <phase>Fase 2</phase> <phase_filter>None</phase_filter> <properties> <property> <name>Id</name> <lookup_1_type></lookup_1_type> <lookup_1_id></lookup_1_id> <type>BUILT_IN_PARAMETER</type> <id>ID_PARAM</id> </property> <property> <name>Family Name</name> <lookup_1_type>BUILT_IN_PARAMETER</lookup_1_type> <lookup_1_id>SYMBOL_ID_PARAM</lookup_1_id> <type>BUILT_IN_PARAMETER</type> <id>ALL_MODEL_FAMILY_NAME</id> </property> <property> <name>Type Name</name> <lookup_1_type>BUILT_IN_PARAMETER</lookup_1_type> <lookup_1_id>SYMBOL_ID_PARAM</lookup_1_id> <type>CALCULATED_PROPERTY</type> <id>TypeName</id> </property> </properties> </link> <link> <name>Furniture Types</name> <description></description> <elements>FurnitureTypes</elements> <phase>Fase 2</phase> <phase_filter>None</phase_filter> <properties> <property> <name>Id</name> <lookup_1_type></lookup_1_type> <lookup_1_id></lookup_1_id> <type>BUILT_IN_PARAMETER</type> <id>ID_PARAM</id> </property> <property> <name>Family Name</name> <lookup_1_type></lookup_1_type> <lookup_1_id></lookup_1_id> <type>CALCULATED_PROPERTY</type> <id>FamilyName</id> </property> <property> <name>Type Name</name> <lookup_1_type></lookup_1_type> <lookup_1_id></lookup_1_id> <type>CALCULATED_PROPERTY</type> <id>TypeName</id> </property> </properties> </link> <link> <name>Furniture System Types</name> <description></description> <elements>FurnitureSystemTypes</elements> <phase>Fase 2</phase> <phase_filter>None</phase_filter> <properties> <property> <name>Id</name> <lookup_1_type></lookup_1_type> <lookup_1_id></lookup_1_id> <type>BUILT_IN_PARAMETER</type> <id>ID_PARAM</id> </property> <property> <name>Family Name</name> <lookup_1_type></lookup_1_type> <lookup_1_id></lookup_1_id> <type>CALCULATED_PROPERTY</type> <id>FamilyName</id> </property> <property> <name>Type Name</name> <lookup_1_type></lookup_1_type> <lookup_1_id></lookup_1_id> <type>CALCULATED_PROPERTY</type> <id>TypeName</id> </property> </properties> </link> <link> <name>Sheets</name> <description></description> <elements>Sheets</elements> <phase>Fase 1</phase> <phase_filter>None</phase_filter> <properties> <property> <name>Id</name> <lookup_1_type></lookup_1_type> <lookup_1_id></lookup_1_id> <type>BUILT_IN_PARAMETER</type> <id>ID_PARAM</id> </property> </properties> </link> <link> <name>Walls</name> <description></description> <elements>WallInstances</elements> <phase>Fase 2</phase> <phase_filter>None</phase_filter> <properties> <property> <name>Id</name> <lookup_1_type></lookup_1_type> <lookup_1_id></lookup_1_id> <type>BUILT_IN_PARAMETER</type> <id>ID_PARAM</id> </property> </properties> </link> <link> <name>Wall types all official names</name> <description></description> <elements>WallTypes</elements> <phase>Fase 1</phase> <phase_filter>None</phase_filter> <properties> <property> <name>Id</name> <lookup_1_type></lookup_1_type> <lookup_1_id></lookup_1_id> <type>BUILT_IN_PARAMETER</type> <id>ID_PARAM</id> </property> <property> <name>Family Name</name> <lookup_1_type></lookup_1_type> <lookup_1_id></lookup_1_id> <type>BUILT_IN_PARAMETER</type> <id>ALL_MODEL_FAMILY_NAME</id> </property> <property> <name>Type Name</name> <lookup_1_type></lookup_1_type> <lookup_1_id></lookup_1_id> <type>CALCULATED_PROPERTY</type> <id>TypeName</id> </property> </properties> </link> <link> <name>test</name> <description></description> <elements>WallTypes</elements> <phase>Fase 1</phase> <phase_filter>None</phase_filter> <properties> <property> <name>Id</name> <lookup_1_type></lookup_1_type> <lookup_1_id></lookup_1_id> <type>BUILT_IN_PARAMETER</type> <id>ID_PARAM</id> </property> <property> <name>Family Name</name> <lookup_1_type></lookup_1_type> <lookup_1_id></lookup_1_id> <type>BUILT_IN_PARAMETER</type> <id>ALL_MODEL_FAMILY_NAME</id> </property> <property> <name>Type Name</name> <lookup_1_type></lookup_1_type> <lookup_1_id></lookup_1_id> <type>CALCULATED_PROPERTY</type> <id>TypeName</id> </property> </properties> </link> </links></application>
Text - 01_Modellfil: va006-a-220-1-0001.rvt
Identity Data - Workset: Project Info
Other - RIE, firma: RAMBØLL AS; Project Status: TU 2013; Saksbehandler: MR; Project Address: Skriv adresse her; Category: Project Information; Prosjektansvarlig: TILBUD E203 TETT BYGG; RIV, telefon: +47 7310 6200; RIB, telefon: +47 7289 3750; Project Name: Trondheim Lufthavn Værnes; RIV, firma: MULTICONSULT AS; RIB, firma: NORCONSULT; RIE, telefon: +47 7389 1000

# IfcBuildingStorey: Level:TA (2)
Identity Data(Type) - Workset: Level Types; Type Name: TA
Graphics(Type) - Symbol: NSW Kote - Triangel med kote, ISO 2,5 mm (fault, do not use -DC) : NSW Kote - Triangel med kote, ISO 2,5 mm; Line Pattern: Centre; Color: 0; Symbol at End 1 Default: yes; Symbol at End 2 Default: no; Line Weight: 4
Constraints(Type) - Elevation Base: Project Base Point
Identity Data - Structural: no; Building Story: yes; Etasje Klassifisering: Hovedetasje; Workset: Shared Levels and Grids
Pset_AirSideSystemInformation - sets with these values: 2
Other - Family and Type: Level: TA; Type Id: 7724934; Type: TA; Category: Levels; Family: Level
Other(Type) - Category: Levels; Family Name: Level
Name | LongName = Identity Data, Name = Pset_AirSideSystemInformation, Name | Elevation (mm) = Constraints, Elevation (mm) | Computation Height (mm)
U01 Hovedetasje | U01 Hovedetasje | 6250 | 1320
H01 Hovedetasje | H01 Hovedetasje | 9320 | 1860

# IfcBuildingStorey: Level:TB (4)
Graphics(Type) - Symbol: NSW Kote - Triangel med kote, ISO 2,5 mm (fault, do not use -DC) : NSW Kote - Triangel med kote, ISO 2,5 mm; Line Pattern: Centre; Color: 0; Symbol at End 1 Default: yes; Symbol at End 2 Default: no; Line Weight: 4
Identity Data - Structural: no; Building Story: yes
Other - Family and Type: Level: TB; Type: TB; Type Id: 7617874; Category: Levels; Family: Level
Constraints(Type) - Elevation Base: Project Base Point
Identity Data(Type) - Workset: Level Types; Type Name: TB
Other(Type) - Category: Levels; Family Name: Level
Name | LongName = Identity Data, Name | Elevation (mm) = Constraints, Elevation (mm) | Computation Height (mm) | Workset
XX - C +7,57 TB U1 | XX - C +7,57 TB U1 | 7570 | 1200 | Shared Levels and Grids | Pset_AirSideSystemInformation - Name: XX - C +7,57 TB U1; sets with these values: 2
XX - C+10,65 TB E1 | XX - C+10,65 TB E1 | 10650 | 1200 | XTB Terminal B | Pset_ProductRequirements - Name: XX - C+10,65 TB E1; sets with these values: 2
XX - C +13,22 TB U/S BEAM | XX - C +13,22 TB U/S BEAM | 13220 | 0 | XTB Terminal B | Pset_ProductRequirements - Name: XX - C +13,22 TB U/S BEAM; sets with these values: 2; Identity Data - TB Workset: yes
C + 13,87 TB E2 | C + 13,87 TB E2 | 13870 | 1200 | Shared Levels and Grids | Pset_AirSideSystemInformation - Name: C + 13,87 TB E2; sets with these values: 2

# IfcBeam: M_Concrete-Rectangular Beam:350X420 (2)
In: XX - C +13,22 TB U/S BEAM
Type - PredefinedType: BEAM; Material: <Unnamed>
Type - Other - Category: Structural Framing; Family Name: M_Concrete-Rectangular Beam
Type - Dimensions - b: 350 mm; h: 420 mm
Type - Identity Data - OmniClass Number: 23.25.30.11.14.14; OmniClass Title: Beams; Type Name: 350X420; Workset: Family : Structural Framing : M_Concrete-Rectangular Beam
Type - Structural - Section Shape: 0
Type - Pset_BeamCommon - IsExternal: no; LoadBearing: yes
Dimensions - Elevation at Bottom: 13220 mm; Elevation at Top: 13640 mm
Identity Data - Has Association: yes; TB Workset: yes; Workset: XTB Terminal B
ePset_SimplebimBasicQuantities - Width (Simplebim): 350 mm; Height (Simplebim): 420 mm
Geometric Position - Join Status: Both joins enabled; yz Justification: Uniform; y Justification: Origin; y Offset Value: 0 mm; z Offset Value: 0 mm; z Justification: Bottom
Structural - Start Attachment Type: End Elevation; Rebar Cover - Bottom Face: Rebar Cover 1 <25 mm>; Rebar Cover - Other Faces: Rebar Cover 1 <25 mm>; Rebar Cover - Top Face: Rebar Cover 1 <25 mm>
Constraints - Reference Level: XX - C +13,22 TB U/S BEAM; Cross-Section Rotation: 0 deg; End Level Offset: 0 mm; Start Level Offset: 0 mm; Work Plane: Level : XX - C +13,22 TB U/S BEAM; Reference Level Elevation: 13220 mm; Orientation: Normal
Other - Family: M_Concrete-Rectangular Beam; Type Id: 16119173; Type: 350X420; Family and Type: M_Concrete-Rectangular Beam: 350X420
Pset_QuantityTakeOff - Reference: 350X420; sets with these values: 2
Phasing - Phase Created: Som Bygget
ePset_Simplebim - Assembly Level: Leaf
Pset_BeamCommon - Slope: 0 deg; Reference: 350X420
ePset_LocationTool - Splitting: ORIGINAL
Name (M_Concrete-Rectangular Beam:350X420:...) | Length (mm) = Span (mm) | Volume (m3) = Volume, net (Simplebim) (m3) | Length (Simplebim) (mm) = Cut Length (mm) | Area, sides, net (Simplebim) (m2) | Weight, as steel (Simplebim) (kg) | Structural Usage
16122152 | 4337.5 | 0.534712 | 4337.5 | 6.48375 | 4197.49 | Other
16122186 | 4225 | 0.569625 | 3875 | 6.2615 | 4471.56 | Girder | Structural - End Attachment Type: End Elevation

# IfcColumn: NSW Søyle - Betong firkantet:350 x 350 mm (16)
Type - PredefinedType: COLUMN; Material: <Unnamed>
Type - Other - Category: Structural Columns; Family Name: NSW Søyle - Betong firkantet
Type - Dimensions - b: 350 mm
Type - Identity Data - Type Name: 350 x 350 mm; Workset: Family : Structural Columns : NSW Søyle - Betong firkantet
Type - Structural - Section Shape: 0
Type - Pset_ColumnCommon - IsExternal: no; LoadBearing: yes
Structural - Rebar Cover - Bottom Face: Rebar Cover 1 <25 mm>; Rebar Cover - Other Faces: Rebar Cover 1 <25 mm>; Rebar Cover - Top Face: Rebar Cover 1 <25 mm>
Pset_ColumnCommon - Reference: 350 x 350 mm
Pset_QuantityTakeOff - Reference: 350 x 350 mm; sets with these values: 2
Phasing - Phase Created: Som Bygget
Other - Family: NSW Søyle - Betong firkantet; Family and Type: NSW Søyle - Betong firkantet: 350 x 350 mm; Type Id: 260131; Type: 350 x 350 mm
Identity Data - Has Association: yes; TB Workset: yes; Workset: XTB Terminal B
ePset_SimplebimBasicQuantities - Width (Simplebim): 350 mm; Depth (Simplebim): 350 mm
Constraints - Room Bounding: yes; Moves With Grids: yes; Column Style: Vertical
ePset_Simplebim - Assembly Level: Leaf
Name (NSW Søyle - Betong firkantet:350 x 350 mm:...) | In | Splitting | Volume, net (Simplebim) (m3) | Weight, as steel (Simplebim) (kg) | Height (Simplebim) (mm) | Area, sides, net (Simplebim) (m2) | Column Location Mark | Top Level | Base Level = Level
453737 | XX - C+10,65 TB E1 | ORIGINAL | 0.39445 | 3096.43 | 3220 | 4.508 | B14-BG | C + 13,87 TB E2 | XX - C+10,65 TB E1 | Constraints - Base Offset: 0 mm; Top Offset: 0 mm; Dimensions - Volume: 0.39445 m3; Length: 3220 mm
453759 | XX - C+10,65 TB E1 | ORIGINAL | 0.39445 | 3096.43 | 3220 | 4.508 | B13-BG | C + 13,87 TB E2 | XX - C+10,65 TB E1 | Constraints - Base Offset: 0 mm; Top Offset: 0 mm; Dimensions - Volume: 0.39445 m3; Length: 3220 mm
454291 | XX - C+10,65 TB E1 | ORIGINAL | 0.39445 | 3096.43 | 3220 | 4.508 | B14-BF+(-785) | C + 13,87 TB E2 | XX - C+10,65 TB E1 | Constraints - Base Offset: 0 mm; Top Offset: 0 mm; Dimensions - Volume: 0.39445 m3; Length: 3220 mm
454301 | XX - C+10,65 TB E1 | ORIGINAL | 0.39445 | 3096.43 | 3220 | 4.508 | B13-BF+(-785) | C + 13,87 TB E2 | XX - C+10,65 TB E1 | Constraints - Base Offset: 0 mm; Top Offset: 0 mm; Dimensions - Volume: 0.39445 m3; Length: 3220 mm
488707 | XX - C+10,65 TB E1 | ORIGINAL | 0.39445 | 3096.43 | 3220 | 4.508 | B13-BF+(-310) | C + 13,87 TB E2 | XX - C+10,65 TB E1 | Constraints - Base Offset: 0 mm; Top Offset: 0 mm; Dimensions - Volume: 0.39445 m3; Length: 3220 mm
16246880 | XX - C+10,65 TB E1 | ORIGINAL | 0.39445 | 3096.43 | 3220 | 4.508 | B13-BF | C + 13,87 TB E2 | XX - C+10,65 TB E1 | Constraints - Base Offset: 0 mm; Top Offset: 0 mm; Dimensions - Volume: 0.39445 m3; Length: 3220 mm
16246924 | XX - C+10,65 TB E1 | ORIGINAL | 0.39445 | 3096.43 | 3220 | 4.508 | B14-BF | C + 13,87 TB E2 | XX - C+10,65 TB E1 | Constraints - Base Offset: 0 mm; Top Offset: 0 mm; Dimensions - Volume: 0.39445 m3; Length: 3220 mm
18547938 | XX - C+10,65 TB E1 | ORIGINAL | 0.34545 | 2711.78 | 2820 | 3.948 | B14-BE | XX - C +18,10 TB Tak | XX - C+10,65 TB E1 | Constraints - Base Offset: 0 mm; Top Offset: -4630 mm; Dimensions - Volume: 0.34545 m3; Length: 2820 mm
18550637 | XX - C+10,65 TB E1 | RESULT | 0.449575 | 3529.16 | 3670 | 5.138 | B13-BE | XX - C +18,10 TB Tak | XX - C+10,65 TB E1 | Constraints - Top is Attached: yes; Construction - Attachment Justification At Top: Minimum Intersection
443101 | XX - C +7,57 TB U1 | RESULT | 0.162925 | 1278.96 | 1330 | 1.862 | B13-BE | XX - C+10,65 TB E1 | XX - C +7,57 TB U1
443111 | XX - C +7,57 TB U1 | RESULT | 0.162925 | 1278.96 | 1330 | 1.862 | B13-BF+(-510) | XX - C+10,65 TB E1 | XX - C +7,57 TB U1
443123 | XX - C +7,57 TB U1 | RESULT | 0.162925 | 1278.96 | 1330 | 1.862 | B13-BG | XX - C+10,65 TB E1 | XX - C +7,57 TB U1
18571224 | XX - C +7,57 TB U1 | RESULT | 0.162925 | 1278.96 | 1330 | 1.862 | B13-BF | XX - C+10,65 TB E1 | XX - C +7,57 TB U1
18571649 | XX - C +7,57 TB U1 | RESULT | 0.162925 | 1278.96 | 1330 | 1.862 | B14-BF+(-510) | XX - C+10,65 TB E1 | XX - C +7,57 TB U1
18571650 | XX - C +7,57 TB U1 | RESULT | 0.162925 | 1278.96 | 1330 | 1.862 | B14-BG | XX - C+10,65 TB E1 | XX - C +7,57 TB U1
18571654 | XX - C +7,57 TB U1 | RESULT | 0.162925 | 1278.96 | 1330 | 1.862 | B14-BF | XX - C+10,65 TB E1 | XX - C +7,57 TB U1

# IfcColumn: NSW Søyle - Betong rektangulær:350 x 175 mm (4)
Type - PredefinedType: COLUMN; Material: _NSW Betong
Type - Other - Category: Structural Columns; Family Name: NSW Søyle - Betong rektangulær
Type - Identity Data - Type Name: 350 x 175 mm; Workset: Family : Structural Columns : NSW Søyle - Betong rektangulær
Type - Structural - Section Shape: 0
Type - Pset_ColumnCommon - IsExternal: no; LoadBearing: yes
Type - Dimensions - Bredde: 175 mm; Dybde: 350 mm
Structural - Rebar Cover - Bottom Face: Rebar Cover 1 <25 mm>; Rebar Cover - Other Faces: Rebar Cover 1 <25 mm>; Rebar Cover - Top Face: Rebar Cover 1 <25 mm>
Other - Family: NSW Søyle - Betong rektangulær; Type: 350 x 175 mm; Family and Type: NSW Søyle - Betong rektangulær: 350 x 175 mm; Type Id: 479843
Materials and Finishes - Structural Material: _NSW Betong
Constraints - Room Bounding: yes; Moves With Grids: yes; Column Style: Vertical
ePset_SimplebimBasicQuantities - Depth (Simplebim): 350 mm; Width (Simplebim): 175 mm
Phasing - Phase Created: Som Bygget
Pset_ReinforcementBarPitchOfColumn - Reference: 350 x 175 mm; sets with these values: 2
Pset_ColumnCommon - Reference: 350 x 175 mm
Identity Data - Has Association: yes; TB Workset: yes; Workset: XTB Terminal B
ePset_Simplebim - Assembly Level: Leaf
Name (NSW Søyle - Betong rektangulær:350 x 175 mm:...) | In | Top Level | Column Location Mark | Base Level = Level | Area, sides, net (Simplebim) (m2) | Volume, net (Simplebim) (m3) | Weight, as steel (Simplebim) (kg) | Height (Simplebim) (mm) | Splitting
488745 | XX - C+10,65 TB E1 | C + 13,87 TB E2 | B14-BF(287) | XX - C+10,65 TB E1 | 3.381 | 0.197225 | 1548.22 | 3220 | ORIGINAL | Dimensions - Volume: 0.197225 m3; Length: 3220 mm; Constraints - Base Offset: 0 mm; Top Offset: 0 mm
16470980 | XX - C+10,65 TB E1 | C + 13,87 TB E2 | B13-BF(287) | XX - C+10,65 TB E1 | 3.381 | 0.197225 | 1548.22 | 3220 | ORIGINAL | Dimensions - Volume: 0.197225 m3; Length: 3220 mm; Constraints - Base Offset: 0 mm; Top Offset: 0 mm
517881 | C + 13,87 TB E2 | XX - C +18,10 TB Tak | B13-BF(288) | C + 13,87 TB E2 | 0.4725 | 0.0275625 | 216.366 | 450 | RESULT | Constraints - Top is Attached: yes; Construction - Attachment Justification At Top: Minimum Intersection
517891 | C + 13,87 TB E2 | XX - C +18,10 TB Tak | B14-BF(288) | C + 13,87 TB E2 | 0.4725 | 0.0275625 | 216.366 | 450 | RESULT | Constraints - Top is Attached: yes; Construction - Attachment Justification At Top: Minimum Intersection

# IfcCovering: Compound Ceiling:V_Terminal B_1200X600 (2)
In: XX - C+10,65 TB E1
Type - PredefinedType: CEILING
Type - Other - Category: Ceilings; Family Name: Compound Ceiling
Type - Construction - Thickness: 60 mm
Type - Graphics - Coarse Scale Fill Color: 0
Type - Identity Data - Type Name: V_Terminal B_1200X600; Workset: Ceiling Types
Type - Text - Himling Kode: 600X1200 SYSTEMHIMLING
Type - Analytical Properties - Roughness: 1; Absorptance: 0.1
Type - Pset_CoveringCommon - TotalThickness: 60 mm
Pset_QuantityTakeOff - Reference: V_Terminal B_1200X600
ePset_SimplebimBasicQuantities - Height (Simplebim): 60 mm
Phasing - Phase Created: Som Bygget
Other - Type: V_Terminal B_1200X600; Family: Compound Ceiling; Type Id: 8181093; Family and Type: Compound Ceiling: V_Terminal B_1200X600
Identity Data - AP3 COMMUTER: no; TB Workset: yes; Workset: XTB Terminal B
Pset_CoveringCommon - Reference: V_Terminal B_1200X600; Finish: Værnes_Ceiling Grid 600 x 1200mm;
ePset_LocationTool - Splitting: RESULT
Constraints - Room Bounding: yes; Level: XX - C+10,65 TB E1
ePset_Simplebim - Assembly Level: Leaf
Name (Compound Ceiling:V_Terminal B_1200X600:...) | Volume, net (Simplebim) (m3) | Width (Simplebim) (mm) | Length (Simplebim) (mm) | Area, largest surface, net (Simplebim) (m2)
16469124 | 0.636813 | 3037 | 3495 | 10.6136
16469202 | 1.30854 | 3489 | 6250 | 21.809

# IfcDoor: V_Generic Sgle Int:1000 x 2100mm, V_Generic Sgle Int:1000 x 2100mm:18550646
In: H01 Hovedetasje
Type - OperationType: SINGLE_SWING_RIGHT; ParameterTakesPrecedence: no; Sizeable: no; Material: N_Door - Handle
Type - IfcDoorPanelProperties - PanelOperation: SWINGING
Type - Other - Category: Doors; Family Name: V_Generic Sgle Int
Type - Construction - Function: Interior; Wall Closure: By host
Type - Dimensions - Frame Depth: 92 mm; Frame Thickness: 42 mm; Height: 2090 mm; Width: 1000 mm
Type - Identity Data - EKS dør tag: EKS; NTI_QuantityDoorSwingLeft: 22; NTI_QuantityDoorSwingRight: 22; Type Mark: 52; Type Name: 1000 x 2100mm; Workset: Family : Doors : V_Generic Sgle Int
Type - Analytical Properties - Define Thermal Properties by: Schematic Type; Analytic Construction: <None>
Type - Pset_DoorCommon - IsExternal: no
OverallHeight: 2100 mm; OverallWidth: 1020 mm
ePset_Simplebim - Assembly Level: Leaf
ePset_LocationTool - Splitting: ORIGINAL
Pset_DoorCommon - Reference: 1000 x 2100mm
Phasing - Phase Created: Som Bygget
Identity Data - Mark: 1WC.381; Workset: XTB Terminal B
ePset_SimplebimBasicQuantities - Area, opening (Simplebim): 2.142 m2; Width, opening (Simplebim): 1020 mm; Width (Simplebim): 1000 mm; Height (Simplebim): 2080 mm; Height, opening (Simplebim): 2100 mm; Length, frame (Simplebim): 5160 mm; Area (Simplebim): 2.08 m2
Pset_QuantityTakeOff - Reference: 1000 x 2100mm
Dimensions - Area: 2.77196 m2; Volume: 0.0953368 m3; Placement: 0 mm; Joint: 10 mm; Joint Threshold: 10 mm
Other - Host Id: 18550643; Family and Type: V_Generic Sgle Int: 1000 x 2100mm; Family: V_Generic Sgle Int; Type: 1000 x 2100mm; Head Height: 2090 mm; Type Id: 750688
Constraints - Level: H01 Hovedetasje; Sill Height: 0 mm

# IfcSlab: Floor:TB_Betong EKS., Floor:TB_Betong EKS.:14343796
In: H01 Hovedetasje
Type - PredefinedType: FLOOR; Material: _NSW Betong 113.2 mm
Type - Other - Category: Floors; Family Name: Floor
Type - Construction - Function: Interior; Default Thickness: 113.2 mm
Type - Graphics - Coarse Scale Fill Color: 0
Type - Identity Data - Type Name: TB_Betong EKS.; Workset: Floor Types
Type - Materials and Finishes - Structural Material: _NSW Betong
Type - Text - Gulv Code: -
Type - Analytical Properties - Roughness: 1; Absorptance: 0.1
Type - Pset_SlabCommon - IsExternal: no
ePset_SimplebimBasicQuantities - Thickness (Simplebim): 113.2 mm; Perimeter (Simplebim): 41385.1 mm; Area, largest surface, net (Simplebim): 106.971 m2; Area, top, net (Simplebim): 106.971 m2; Area, sides, net (Simplebim): 4.6848 m2; Volume, net (Simplebim): 12.1092 m3
ePset_Simplebim - Assembly Level: Leaf
Other - Type Id: 16331105; Type: TB_Betong EKS.; Family and Type: Floor: TB_Betong EKS.; Family: Floor
Constraints - Level: H01 Hovedetasje; Room Bounding: yes; Related to Mass: no
Phasing - Phase Created: Som Bygget
ePset_LocationTool - Splitting: RESULT
Structural - Structural: no
Identity Data - TB Workset: yes; Has Association: no; Workset: XTB Terminal B
Pset_QuantityTakeOff - Reference: TB_Betong EKS.; sets with these values: 2
Pset_SlabCommon - Reference: TB_Betong EKS.; LoadBearing: no

# IfcWall: Basic Wall:TB_SE11/160, Basic Wall:TB_SE11/160:15833101
In: XX - C+10,65 TB E1
Type - PredefinedType: STANDARD; Material: Værnes_Gipsplate 13 mm, Værnes_Stålstender, uisolert 160 mm, Værnes_Gipsplate 13 mm
Type - Other - Category: Walls; Family Name: Basic Wall
Type - Construction - Function: Interior; Width: 186 mm; Wrapping at Inserts: Both
Type - Graphics - Coarse Scale Fill Color: 0
Type - Identity Data - Type Name: TB_SE11/160; Workset: Wall Types
Type - Materials and Finishes - Structural Material: Værnes_Stålstender, uisolert
Type - Analytical Properties - Absorptance: 0.1; Roughness: 1
Type - Pset_WallCommon - IsExternal: no
Type - Text - Core Kode: GS 160/160 (600) N-N M0
ePset_Simplebim - Assembly Level: Leaf
Cross-Section Definition - Cross-Section: Vertical
ePset_LocationTool - Splitting: RESULT
Pset_WallCommon - ExtendToStructure: no; LoadBearing: no; Reference: TB_SE11/160
Structural - Structural Usage: Non-bearing; Structural: no
Other - Family and Type: Basic Wall: TB_SE11/160; Family: Basic Wall; Type Id: 16247128; Type: TB_SE11/160
Phasing - Phase Created: Som Bygget
ePset_SimplebimBasicQuantities - Area, largest surface, net (Simplebim): 19.9383 m2; Thickness (Simplebim): 186 mm; Height (Simplebim): 3010 mm; Length (Simplebim): 6744 mm; Volume, net (Simplebim): 3.75988 m3; Area, side, gross, AABB (Simplebim): 20.2994 m2; Area, side, net, smaller (Simplebim): 20.2144 m2; Area, side, gross, smaller (Simplebim): 20.2144 m2; Area, side, net, average (Simplebim): 20.2144 m2; Area, side, gross, average (Simplebim): 20.2144 m2; Area, side, gross, larger (Simplebim): 20.2144 m2; Area, side, net, larger (Simplebim): 20.2144 m2
Pset_ReinforcementBarPitchOfWall - Reference: TB_SE11/160; sets with these values: 2
Constraints - Room Bounding: yes; Base is Attached: no; Related to Mass: no; Top is Attached: no; Location Line: Core Centerline; Base Constraint: XX - C+10,65 TB E1
Identity Data - TB Workset: yes; Workset: XTB Terminal B

# IfcWall: Basic Wall:TB_SKJØRT 95mm, Basic Wall:TB_SKJØRT 95mm:624599
In: XX - C+10,65 TB E1
Type - PredefinedType: STANDARD; Material: Værnes_Gipsplate 13 mm, Værnes_Stender 95 mm, Værnes_Gipsplate 13 mm
Type - Other - Category: Walls; Family Name: Basic Wall
Type - Construction - Function: Exterior; Width: 121 mm; Wrapping at Inserts: Do not wrap
Type - Graphics - Coarse Scale Fill Color: 0
Type - Identity Data - Type Name: TB_SKJØRT 95mm; Workset: Wall Types
Type - Materials and Finishes - Structural Material: Værnes_Stender
Type - Analytical Properties - Absorptance: 0.1; Roughness: 1
Type - Pset_WallCommon - IsExternal: yes
Type - Text - Core Kode: SKØRT - GS 95/95 (600) N-N
ePset_SimplebimBasicQuantities - Area, largest surface, net (Simplebim): 9.15807 m2; Area, side, gross, average (Simplebim): 9.15807 m2; Area, side, net, average (Simplebim): 9.15807 m2; Area, side, gross, smaller (Simplebim): 9.15807 m2; Area, side, net, larger (Simplebim): 9.15807 m2; Area, side, net, smaller (Simplebim): 9.15807 m2; Area, side, gross, larger (Simplebim): 9.15807 m2; Area, side, gross, AABB (Simplebim): 9.15798 m2; Volume, net (Simplebim): 1.10813 m3; Thickness (Simplebim): 121 mm; Height (Simplebim): 907 mm; Length (Simplebim): 10097 mm
ePset_Simplebim - Assembly Level: Leaf
Cross-Section Definition - Cross-Section: Vertical
Constraints - Location Line: Wall Centerline; Room Bounding: yes; Base is Attached: no; Related to Mass: no; Top is Attached: no; Base Constraint: XX - C+10,65 TB E1
Structural - Structural Usage: Non-bearing; Structural: no
Phasing - Phase Created: Som Bygget
Pset_WallCommon - ExtendToStructure: no; LoadBearing: no; Reference: TB_SKJØRT 95mm
Pset_ReinforcementBarPitchOfWall - Reference: TB_SKJØRT 95mm; sets with these values: 2
Other - Family: Basic Wall; Type Id: 16208739; Family and Type: Basic Wall: TB_SKJØRT 95mm; Type: TB_SKJØRT 95mm
ePset_LocationTool - Splitting: RESULT
Identity Data - TB Workset: yes; Workset: XTB Terminal B

# IfcWall: Basic Wall:V_Existing 100mm (4)
In: C + 13,87 TB E2
Type - PredefinedType: STANDARD; Material: Existing - Bridget key 100 mm
Type - Other - Category: Walls; Family Name: Basic Wall
Type - Construction - Function: Interior; Width: 100 mm; Wrapping at Inserts: Both
Type - Graphics - Coarse Scale Fill Color: 0
Type - Identity Data - Type Name: V_Existing 100mm; Workset: Wall Types
Type - Materials and Finishes - Structural Material: Existing - Bridget key
Type - Analytical Properties - Absorptance: 0.1; Roughness: 1
Type - Pset_WallCommon - IsExternal: no
Type - Text - Core Kode: EKS; Vegg Kode: EKS
Constraints - Location Line: Wall Centerline; Room Bounding: yes; Base is Attached: no; Related to Mass: no; Top is Attached: yes; Base Constraint: C + 13,87 TB E2
ePset_Simplebim - Assembly Level: Leaf
Cross-Section Definition - Cross-Section: Vertical
ePset_SimplebimBasicQuantities - Thickness (Simplebim): 100 mm; Height (Simplebim): 450 mm
ePset_LocationTool - Splitting: RESULT
Structural - Structural Usage: Non-bearing; Structural: no
Phasing - Phase Created: Som Bygget
Pset_WallCommon - Reference: V_Existing 100mm; ExtendToStructure: yes; LoadBearing: no
Other - Type: V_Existing 100mm; Family: Basic Wall; Type Id: 204692; Family and Type: Basic Wall: V_Existing 100mm
Pset_QuantityTakeOff - Reference: V_Existing 100mm; sets with these values: 2
Identity Data - TB Workset: yes; Workset: XTB Terminal B
Name (Basic Wall:V_Existing 100mm:...) | Area, side, gross, AABB (Simplebim) (m2) | Length (Simplebim) (mm) | Area, side, net, average (Simplebim) (m2) = Area, largest surface, net (Simplebim) (m2) = Area, side, gross, average (Simplebim) (m2) = Area, side, net, smaller (Simplebim) (m2) = Area, side, gross, larger (Simplebim) (m2) = Area, side, gross, smaller (Simplebim) (m2) = Area, side, net, larger (Simplebim) (m2) | Volume, net (Simplebim) (m3) | Top Constraint
624660 | 2.31075 | 5135 | 2.28655 | 0.228655
649661 | 0.7911 | 1758 | 0.790931 | 0.0790931 | Up to level: XX - C +18,10 TB Tak
649662 | 0.46755 | 1039 | 0.467719 | 0.0467719 | Up to level: XX - C +18,10 TB Tak
649663 | 2.8125 | 6250 | 2.8125 | 0.28125 | Up to level: XX - C +18,10 TB Tak

# IfcWall: Basic Wall:V_Existing 120mm (3)
In: H01 Hovedetasje
Type - PredefinedType: STANDARD; Material: Existing - Bridget key 120 mm
Type - Other - Category: Walls; Family Name: Basic Wall
Type - Construction - Function: Exterior; Width: 120 mm; Wrapping at Inserts: Do not wrap
Type - Graphics - Coarse Scale Fill Color: 0
Type - Identity Data - Type Name: V_Existing 120mm; Workset: Wall Types
Type - Materials and Finishes - Structural Material: Existing - Bridget key
Type - Analytical Properties - Absorptance: 0.1; Roughness: 1
Type - Pset_WallCommon - IsExternal: yes
ePset_SimplebimBasicQuantities - Thickness (Simplebim): 120 mm; Height (Simplebim): 3010 mm
ePset_Simplebim - Assembly Level: Leaf
Pset_WallCommon - Reference: V_Existing 120mm; ExtendToStructure: no; LoadBearing: no
Cross-Section Definition - Cross-Section: Vertical
Pset_ReinforcementBarPitchOfWall - Reference: V_Existing 120mm; sets with these values: 2
Other - Type Id: 4523678; Type: V_Existing 120mm; Family: Basic Wall; Family and Type: Basic Wall: V_Existing 120mm
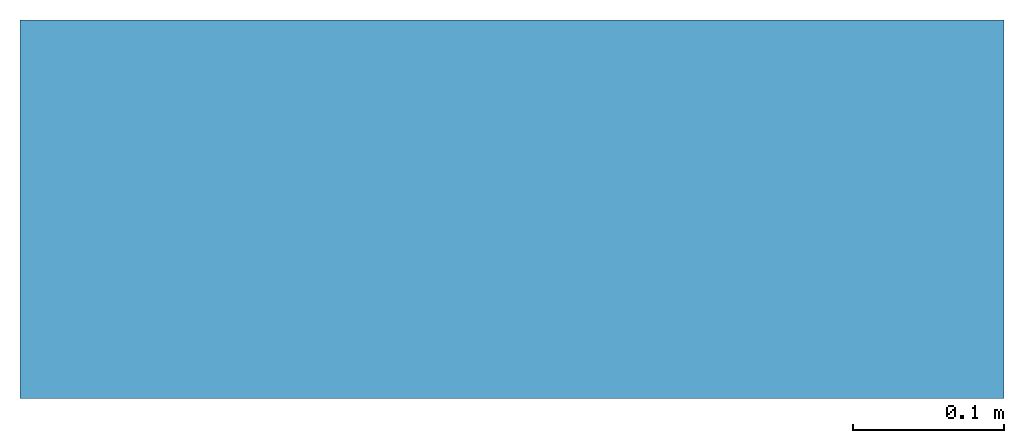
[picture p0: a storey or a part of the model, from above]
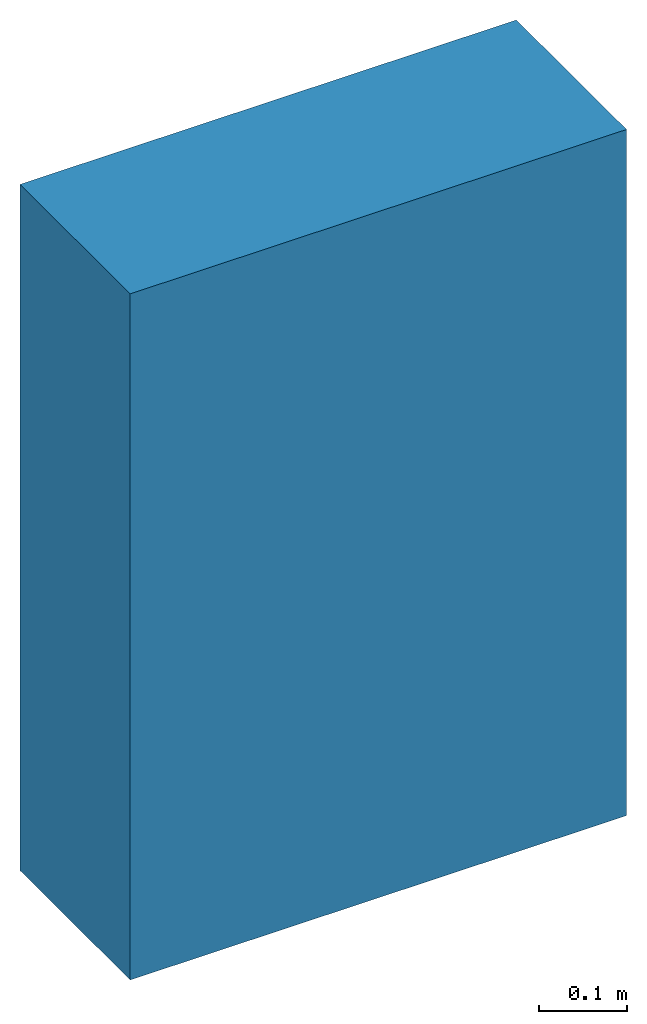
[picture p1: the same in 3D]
Properties of the parts of a building model (IFC2X3), part 2 of 2

# IfcWall: Basic Wall:V_Existing 120mm (3)
Structural - Structural Usage: Non-bearing; Structural: no
Phasing - Phase Created: Som Bygget
Constraints - Base Constraint: H01 Hovedetasje; Room Bounding: yes; Base is Attached: no; Related to Mass: no; Top is Attached: no; Location Line: Finish Face: Interior
Identity Data - Workset: XTB Terminal B
Name (Basic Wall:V_Existing 120mm:...) | Area, largest surface, net (Simplebim) (m2) = Area, side, gross, average (Simplebim) (m2) = Area, side, net, average (Simplebim) (m2) = Area, side, gross, smaller (Simplebim) (m2) = Area, side, net, larger (Simplebim) (m2) = Area, side, net, smaller (Simplebim) (m2) = Area, side, gross, larger (Simplebim) (m2) | Area, side, gross, AABB (Simplebim) (m2) | Volume, net (Simplebim) (m3) | Length (Simplebim) (mm) | Splitting
18550648 | 10.9907 | 11.1107 | 1.31888 | 3691.25 | ORIGINAL | Constraints - Top Offset: 0 mm; Base Extension Distance: 0 mm; Top Extension Distance: 0 mm; Base Offset: 1330 mm; Unconnected Height: 3010 mm; Dimensions - Area: 10.9907 m2; Volume: 1.31888 m3; Length: 3751.25 mm
18550650 | 9.47247 | 9.47247 | 1.1367 | 3147 | RESULT
18631770 | 23.469 | 23.469 | 2.81628 | 7797 | RESULT

# IfcWall: Basic Wall:V_Existing 150mm (3)
In: XX - C+10,65 TB E1
Type - PredefinedType: STANDARD; Material: Existing - Bridget key 150 mm
Type - Other - Category: Walls; Family Name: Basic Wall
Type - Construction - Function: Exterior; Width: 150 mm; Wrapping at Inserts: Do not wrap
Type - Graphics - Coarse Scale Fill Color: 0
Type - Identity Data - Type Name: V_Existing 150mm; Workset: Wall Types
Type - Materials and Finishes - Structural Material: Existing - Bridget key
Type - Analytical Properties - Absorptance: 0.1; Roughness: 1
Type - Pset_WallCommon - IsExternal: yes
Type - Text - Core Kode: EKS
Pset_ReinforcementBarPitchOfWall - Reference: V_Existing 150mm; sets with these values: 2
Other - Type: V_Existing 150mm; Family: Basic Wall; Type Id: 4520733; Family and Type: Basic Wall: V_Existing 150mm
ePset_Simplebim - Assembly Level: Leaf
Cross-Section Definition - Cross-Section: Vertical
ePset_LocationTool - Splitting: RESULT
Structural - Structural Usage: Non-bearing; Structural: no
Constraints - Location Line: Wall Centerline; Room Bounding: yes; Base is Attached: no; Related to Mass: no; Top is Attached: no; Top Constraint: Up to level: XX - C+10,65 TB E1; Base Constraint: XX - C+10,65 TB E1
Phasing - Phase Created: Som Bygget
ePset_SimplebimBasicQuantities - Thickness (Simplebim): 150 mm; Height (Simplebim): 300 mm
Pset_WallCommon - Reference: V_Existing 150mm; ExtendToStructure: no; LoadBearing: no
Identity Data - TB Workset: yes; Workset: XTB Terminal B
Name (Basic Wall:V_Existing 150mm:...) | Volume, net (Simplebim) (m3) | Area, side, net, smaller (Simplebim) (m2) = Area, side, gross, larger (Simplebim) (m2) = Area, side, gross, smaller (Simplebim) (m2) = Area, side, net, larger (Simplebim) (m2) = Area, side, net, average (Simplebim) (m2) = Area, largest surface, net (Simplebim) (m2) = Area, side, gross, average (Simplebim) (m2) = Area, side, gross, AABB (Simplebim) (m2) | Length (Simplebim) (mm)
1108752 | 0.056115 | 0.3741 | 1247
1108980 | 0.02925 | 0.195 | 650
1109161 | 0.02925 | 0.195 | 650

# IfcWall: Basic Wall:V_Existing 175mm (2)
In: C + 13,87 TB E2
Type - PredefinedType: STANDARD; Material: Existing - Bridget key 175 mm
Type - Other - Category: Walls; Family Name: Basic Wall
Type - Construction - Function: Exterior; Width: 175 mm; Wrapping at Inserts: Do not wrap
Type - Graphics - Coarse Scale Fill Color: 0
Type - Identity Data - Type Name: V_Existing 175mm; Workset: Wall Types
Type - Materials and Finishes - Structural Material: Existing - Bridget key
Type - Analytical Properties - Absorptance: 0.1; Roughness: 1
Type - Pset_WallCommon - IsExternal: yes
Pset_WallCommon - Reference: V_Existing 175mm; ExtendToStructure: yes; LoadBearing: no
Other - Type Id: 4515463; Family: Basic Wall; Type: V_Existing 175mm; Family and Type: Basic Wall: V_Existing 175mm
ePset_LocationTool - Splitting: RESULT
ePset_Simplebim - Assembly Level: Leaf
Cross-Section Definition - Cross-Section: Vertical
Structural - Structural Usage: Non-bearing; Structural: no
Text - Code: TB
Phasing - Phase Created: Som Bygget
ePset_SimplebimBasicQuantities - Thickness (Simplebim): 176 mm; Height (Simplebim): 450 mm
Pset_ReinforcementBarPitchOfWall - Reference: V_Existing 175mm; sets with these values: 2
Constraints - Location Line: Wall Centerline; Top Constraint: Up to level: XX - C +18,10 TB Tak; Room Bounding: yes; Base is Attached: no; Related to Mass: no; Top is Attached: yes; Base Constraint: C + 13,87 TB E2
Identity Data - TB Workset: yes; Workset: XTB Terminal B
Name (Basic Wall:V_Existing 175mm:...) | Area, side, gross, average (Simplebim) (m2) = Area, largest surface, net (Simplebim) (m2) = Area, side, net, average (Simplebim) (m2) = Area, side, net, larger (Simplebim) (m2) = Area, side, gross, smaller (Simplebim) (m2) = Area, side, gross, larger (Simplebim) (m2) = Area, side, net, smaller (Simplebim) (m2) = Area, side, gross, AABB (Simplebim) (m2) | Length (Simplebim) (mm) | Volume, net (Simplebim) (m3)
511991 | 1.41615 | 3147 | 0.247826
512106 | 2.8125 | 6250 | 0.492188

# IfcWall: Basic Wall:V_Existing 250mm (4)
Type - PredefinedType: STANDARD; Material: Existing - Bridget key 250 mm
Type - Other - Category: Walls; Family Name: Basic Wall
Type - Construction - Function: Exterior; Width: 250 mm; Wrapping at Inserts: Do not wrap
Type - Graphics - Coarse Scale Fill Color: 0
Type - Identity Data - Type Name: V_Existing 250mm; Workset: Wall Types
Type - Materials and Finishes - Structural Material: Existing - Bridget key
Type - Analytical Properties - Absorptance: 0.1; Roughness: 1
Type - Pset_WallCommon - IsExternal: yes
ePset_Simplebim - Assembly Level: Leaf
Other - Family: Basic Wall; Type: V_Existing 250mm; Family and Type: Basic Wall: V_Existing 250mm; Type Id: 4518234
Cross-Section Definition - Cross-Section: Vertical
ePset_SimplebimBasicQuantities - Thickness (Simplebim): 250 mm
Structural - Structural Usage: Non-bearing; Structural: no
Constraints - Room Bounding: yes; Base is Attached: no; Related to Mass: no; Top is Attached: no
Phasing - Phase Created: Som Bygget
ePset_LocationTool - Splitting: RESULT
Pset_WallCommon - Reference: V_Existing 250mm; ExtendToStructure: no; LoadBearing: no
Pset_ReinforcementBarPitchOfWall - Reference: V_Existing 250mm; sets with these values: 2
Identity Data - Workset: XTB Terminal B
Name (Basic Wall:V_Existing 250mm:...) | In | Area, side, gross, smaller (Simplebim) (m2) = Area, side, net, larger (Simplebim) (m2) = Area, side, net, smaller (Simplebim) (m2) = Area, side, gross, larger (Simplebim) (m2) = Area, largest surface, net (Simplebim) (m2) = Area, side, gross, average (Simplebim) (m2) = Area, side, net, average (Simplebim) (m2) = Area, side, gross, AABB (Simplebim) (m2) | Volume, net (Simplebim) (m3) | Height (Simplebim) (mm) | Length (Simplebim) (mm) | Location Line | Top Constraint | Base Constraint | TB Workset
1108347 | XX - C+10,65 TB E1 | 3.0291 | 0.757275 | 300 | 10097 | Wall Centerline | Up to level: XX - C+10,65 TB E1 | XX - C+10,65 TB E1 | yes
1108623 | XX - C+10,65 TB E1 | 3.0291 | 0.757275 | 300 | 10097 | Wall Centerline | Up to level: XX - C+10,65 TB E1 | XX - C+10,65 TB E1 | yes
1109280 | XX - C+10,65 TB E1 | 0.195 | 0.04875 | 300 | 650 | Wall Centerline | Up to level: XX - C+10,65 TB E1 | XX - C+10,65 TB E1 | yes
18571939 | U01 Hovedetasje | 0.6175 | 0.154375 | 950 | 650 | Finish Face: Interior |  | U01 Hovedetasje

# IfcWallStandardCase: Basic Wall:V_Existing 120mm (4)
In: H01 Hovedetasje
Type - PredefinedType: STANDARD; Material: Existing - Bridget key 120 mm
Type - Other - Category: Walls; Family Name: Basic Wall
Type - Construction - Function: Exterior; Width: 120 mm; Wrapping at Inserts: Do not wrap
Type - Graphics - Coarse Scale Fill Color: 0
Type - Identity Data - Type Name: V_Existing 120mm; Workset: Wall Types
Type - Materials and Finishes - Structural Material: Existing - Bridget key
Type - Analytical Properties - Absorptance: 0.1; Roughness: 1
Type - Pset_WallCommon - IsExternal: yes
ePset_SimplebimBasicQuantities - Thickness (Simplebim): 120 mm; Height (Simplebim): 3010 mm
ePset_Simplebim - Assembly Level: Leaf
ePset_LocationTool - Splitting: ORIGINAL
Pset_WallCommon - Reference: V_Existing 120mm; ExtendToStructure: no; LoadBearing: no
Cross-Section Definition - Cross-Section: Vertical
Pset_ReinforcementBarPitchOfWall - Reference: V_Existing 120mm; sets with these values: 2
Other - Type Id: 4523678; Type: V_Existing 120mm; Family: Basic Wall; Family and Type: Basic Wall: V_Existing 120mm
Structural - Structural Usage: Non-bearing; Structural: no
Phasing - Phase Created: Som Bygget
Constraints - Base Constraint: H01 Hovedetasje; Top Offset: 0 mm; Room Bounding: yes; Base Extension Distance: 0 mm; Base is Attached: no; Related to Mass: no; Top Extension Distance: 0 mm; Top is Attached: no; Location Line: Finish Face: Interior; Base Offset: 1330 mm; Unconnected Height: 3010 mm
Identity Data - Workset: XTB Terminal B
Name (Basic Wall:V_Existing 120mm:...) | Area, side, net, average (Simplebim) (m2) = Area, largest surface, net (Simplebim) (m2) = Area, side, net, smaller (Simplebim) (m2) = Area, side, net, larger (Simplebim) (m2) = Area (m2) | Area, side, gross, average (Simplebim) (m2) = Area, side, gross, larger (Simplebim) (m2) = Area, side, gross, smaller (Simplebim) (m2) | Area, side, gross, AABB (Simplebim) (m2) | Volume, net (Simplebim) (m3) = Volume (m3) | Length (Simplebim) (mm) | Length (mm)
18550636 | 3.01 | 3.01 | 3.01 | 0.3612 | 1000 | 1093
18550643 | 5.7764 | 7.9184 | 6.5618 | 0.693168 | 2180 | 2273
18550644 | 2.408 | 2.408 | 2.408 | 0.28896 | 800 | 860
18550647 | 9.1504 | 9.1504 | 9.1504 | 1.09805 | 3040 | 3040

# IfcWallStandardCase: Basic Wall:V_Existing 150mm (4)
In: XX - C+10,65 TB E1
Type - PredefinedType: STANDARD; Material: Existing - Bridget key 150 mm
Type - Other - Category: Walls; Family Name: Basic Wall
Type - Construction - Function: Exterior; Width: 150 mm; Wrapping at Inserts: Do not wrap
Type - Graphics - Coarse Scale Fill Color: 0
Type - Identity Data - Type Name: V_Existing 150mm; Workset: Wall Types
Type - Materials and Finishes - Structural Material: Existing - Bridget key
Type - Analytical Properties - Absorptance: 0.1; Roughness: 1
Type - Pset_WallCommon - IsExternal: yes
Type - Text - Core Kode: EKS
Pset_ReinforcementBarPitchOfWall - Reference: V_Existing 150mm; sets with these values: 2
Other - Type: V_Existing 150mm; Family: Basic Wall; Type Id: 4520733; Family and Type: Basic Wall: V_Existing 150mm
ePset_Simplebim - Assembly Level: Leaf
Cross-Section Definition - Cross-Section: Vertical
Structural - Structural Usage: Non-bearing; Structural: no
ePset_LocationTool - Splitting: ORIGINAL
Phasing - Phase Created: Som Bygget
Pset_WallCommon - Reference: V_Existing 150mm; ExtendToStructure: no; LoadBearing: no
Constraints - Top Offset: -100 mm; Base Offset: -400 mm; Location Line: Wall Centerline; Room Bounding: yes; Base Extension Distance: 0 mm; Base is Attached: no; Related to Mass: no; Top Extension Distance: 0 mm; Top is Attached: no; Unconnected Height: 300 mm; Top Constraint: Up to level: XX - C+10,65 TB E1; Base Constraint: XX - C+10,65 TB E1
ePset_SimplebimBasicQuantities - Thickness (Simplebim): 150 mm; Height (Simplebim): 300 mm
Identity Data - TB Workset: yes; Workset: XTB Terminal B
Name (Basic Wall:V_Existing 150mm:...) | Length (mm) | Area (m2) = Area, side, gross, AABB (Simplebim) (m2) = Area, side, gross, larger (Simplebim) (m2) = Area, side, net, smaller (Simplebim) (m2) = Area, side, net, larger (Simplebim) (m2) = Area, side, gross, smaller (Simplebim) (m2) = Area, side, net, average (Simplebim) (m2) = Area, side, gross, average (Simplebim) (m2) = Area, largest surface, net (Simplebim) (m2) | Volume (m3) = Volume, net (Simplebim) (m3) | Length (Simplebim) (mm)
1108792 | 1850 | 0.495 | 0.07425 | 1650
1109028 | 1850 | 0.54 | 0.081 | 1800
1109061 | 2150 | 0.645 | 0.09675 | 2150
1109109 | 1850 | 0.495 | 0.07425 | 1650
